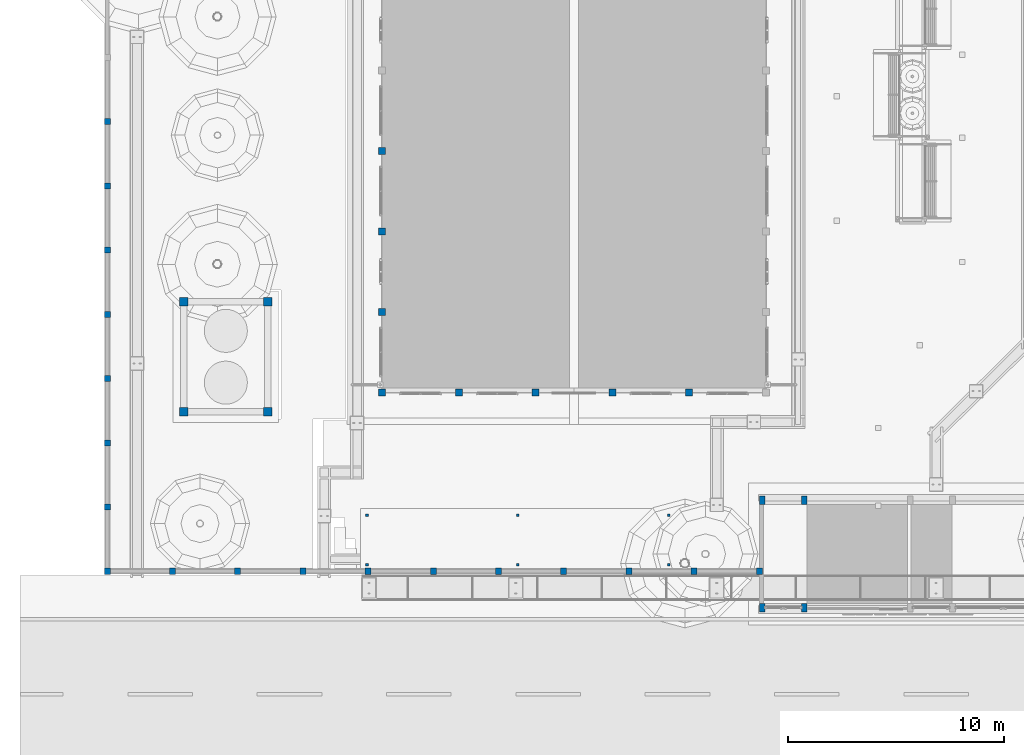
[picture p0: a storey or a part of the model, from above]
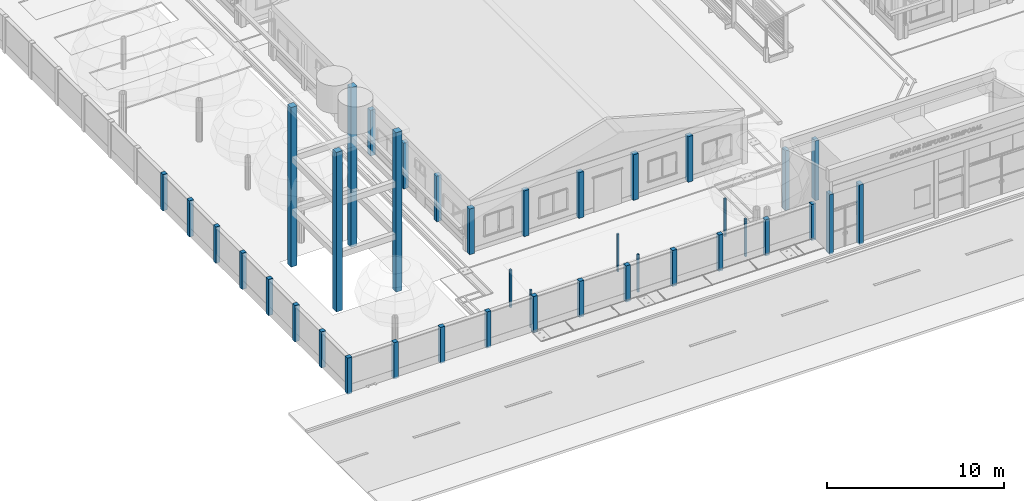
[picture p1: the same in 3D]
Properties of the parts of a building model (IFC4)

# File
Description: ViewDefinition [CoordinationView]
Time: 2026-11-03T15:19:36
Written by: IfcOpenShell 0.9.0post1+b5e509b
Made in: IfcOpenShell 0.9.0post1+b5e509b

# IfcBuildingStorey, NIVEL 1 (NPT +0.00)
In: Hogar de Refugio Temporal
Elevation: 0 m

# IfcBeam: Viga (200)
In: NIVEL 1 (NPT +0.00)
PredefinedType: BEAM
Pset_HogarRefugio - Categoria: Viga
Name | Grupo = Group | Material
E-01_viga | E-01 | TP1
E-02_viga | E-02 | TP1
E-03_viga | E-03 | TP1
E-04_viga | E-04 | TP1
E-05_viga | E-05 | TP1
E-06_viga | E-06 | TP1
E-08_viga | E-08 | TP1
E-07_viga | E-07 | TP1
E-09_viga | E-09 | TP1
2 x travesano | Losa deportiva | blanco
14 x arco | Losa deportiva | acero
133 x diag | Losa deportiva | acero
2 x viga_long | Losa deportiva | acero
oe01_viga | Obras exteriores | TP1
oe01_cielo | Obras exteriores | TP2
oe01_viga_post | Obras exteriores | TP1
8 x tanque_viga | Obras exteriores | concreto_gris
2 x columpio_viga | Obras exteriores | juego_rojo
9 x oc01_viga | Obras exteriores | estructura_acero
18 x oc01_correa | Obras exteriores | estructura_acero

# IfcBuildingElementProxy: Asta de banderas (3)
In: NIVEL 1 (NPT +0.00)
Pset_HogarRefugio - Grupo: Obras exteriores; Categoria: Asta de banderas
Group: Obras exteriores
Name | Material
2 x bandera | bandera_roja
bandera | bandera_blanca

# IfcBuildingElementProxy: Elemento (6)
In: NIVEL 1 (NPT +0.00)
Pset_HogarRefugio - Categoria: Elemento
Name | Grupo = Group | Material
Torus | Losa deportiva | linea
2 x Cylinder | Obras exteriores | negro
3 x Cylinder | Obras exteriores | aluminio_claro

# IfcBuildingElementProxy: Letras "HOGAR DE REFUGIO TEMPORAL", letrero
In: NIVEL 1 (NPT +0.00)
Pset_HogarRefugio - Grupo: Obras exteriores; Categoria: Letras "HOGAR DE REFUGIO TEMPORAL"; Material: aluminio_claro
Group: Obras exteriores

# IfcBuildingElementProxy: Losa deportiva y vía (111)
In: NIVEL 1 (NPT +0.00)
Pset_HogarRefugio - Categoria: Losa deportiva y vía
Name | Grupo = Group | Material
pista | Terreno | asfalto
92 x linea_carril | Terreno | linea
cancha | Losa deportiva | cancha
5 x linea_cancha | Losa deportiva | linea
2 x area | Losa deportiva | cancha_borde
6 x linea_area | Losa deportiva | linea
2 x tablero | Losa deportiva | blanco
2 x brazo | Losa deportiva | acero

# IfcColumn: Columna (386)
In: NIVEL 1 (NPT +0.00)
PredefinedType: COLUMN
Pset_HogarRefugio - Categoria: Columna
Name | Grupo = Group | Material
26 x E-01_col | E-01 | TP1
14 x E-02_col | E-02 | TP1
16 x E-03_col | E-03 | TP1
30 x E-04_col | E-04 | TP1
28 x E-05_col | E-05 | TP1
20 x E-06_col | E-06 | TP1
20 x E-08_col | E-08 | TP1
30 x E-07_col | E-07 | TP1
14 x E-09_col | E-09 | TP1
4 x poste_arco | Losa deportiva | blanco
2 x poste_basquet | Losa deportiva | acero
14 x columna_losa | Losa deportiva | acero
5 x oe01_col | Obras exteriores | TP1
5 x oe01_col_post | Obras exteriores | TP1
6 x poste_autos | Obras exteriores | acero
6 x poste_motos | Obras exteriores | acero
4 x tanque_col | Obras exteriores | concreto_gris
124 x columna_cerco | Obras exteriores | TP2
18 x oc01_columna | Obras exteriores | estructura_acero

# IfcColumn: Falsa columna (45)
In: NIVEL 1 (NPT +0.00)
PredefinedType: COLUMN
Pset_HogarRefugio - Categoria: Falsa columna; Material: concreto_gris
Name | Grupo = Group
9 x oc01_falsa_columna | Obras exteriores
36 x falsa_columna | Drenaje

# IfcDistributionChamberElement: Tapa ciega de registro del colector (28)
In: NIVEL 1 (NPT +0.00)
PredefinedType: INSPECTIONCHAMBER; Group: Drenaje
Pset_HogarRefugio - Grupo: Drenaje; Categoria: Tapa ciega de registro del colector
Name | Material
7 x tapa_junta | negro
7 x tapa_ciega | tapa_concreto
14 x tapa_asa | acero

# IfcDistributionChamberElement: Tapa de inspección (68)
In: NIVEL 1 (NPT +0.00)
PredefinedType: INSPECTIONCHAMBER; Group: Drenaje
Pset_HogarRefugio - Grupo: Drenaje; Categoria: Tapa de inspección
Name | Material
17 x tapa_insp_junta | negro
17 x tapa_inspeccion | tapa_inspeccion
34 x tapa_insp_asa | acero

# IfcDoor: Puerta (108)
In: NIVEL 1 (NPT +0.00)
PredefinedType: DOOR
Pset_HogarRefugio - Categoria: Puerta
Name | Grupo = Group | Material
2 x E-01_pp | E-01 | vidrio
2 x E-01_pp_marco | E-01 | TP1
2 x E-01_p1 | E-01 | puerta
2 x E-01_p1_marco | E-01 | TP1
2 x E-01_p4 | E-01 | puerta
2 x E-01_p4_marco | E-01 | TP1
2 x E-02_pp | E-02 | puerta
2 x E-02_pp_marco | E-02 | TP1
2 x E-02_p1 | E-02 | puerta
2 x E-02_p1_marco | E-02 | TP1
2 x E-03_p1 | E-03 | puerta
2 x E-03_p1_marco | E-03 | TP1
2 x E-03_pp | E-03 | puerta
2 x E-03_pp_marco | E-03 | TP1
2 x E-04_pp | E-04 | puerta
2 x E-04_pp_marco | E-04 | TP1
2 x E-04_p1 | E-04 | puerta
2 x E-04_p1_marco | E-04 | TP1
2 x E-04_p4 | E-04 | puerta
2 x E-04_p4_marco | E-04 | TP1
2 x E-04_p7 | E-04 | puerta
2 x E-04_p7_marco | E-04 | TP1
2 x E-05_pp | E-05 | vidrio
2 x E-05_pp_marco | E-05 | TP1
2 x E-05_p1 | E-05 | puerta
2 x E-05_p1_marco | E-05 | TP1
2 x E-05_p4 | E-05 | puerta
2 x E-05_p4_marco | E-05 | TP1
2 x E-05_p7 | E-05 | puerta
2 x E-05_p7_marco | E-05 | TP1
2 x E-06_p1 | E-06 | puerta
2 x E-06_p1_marco | E-06 | TP1
2 x E-06_p4 | E-06 | puerta
2 x E-06_p4_marco | E-06 | TP1
2 x E-06_pp | E-06 | puerta
2 x E-06_pp_marco | E-06 | TP1
2 x E-08_p1 | E-08 | puerta
2 x E-08_p1_marco | E-08 | TP1
2 x E-08_p4 | E-08 | puerta
2 x E-08_p4_marco | E-08 | TP1
2 x E-08_pp | E-08 | puerta
2 x E-08_pp_marco | E-08 | TP1
2 x E-07_pp | E-07 | puerta
2 x E-07_pp_marco | E-07 | TP1
2 x E-07_p1 | E-07 | puerta
2 x E-07_p1_marco | E-07 | TP1
2 x E-07_p4 | E-07 | puerta
2 x E-07_p4_marco | E-07 | TP1
2 x E-07_p7 | E-07 | puerta
2 x E-07_p7_marco | E-07 | TP1
2 x E-09_pp | E-09 | puerta
2 x E-09_pp_marco | E-09 | TP1
2 x E-09_p1 | E-09 | puerta
2 x E-09_p1_marco | E-09 | TP1

# IfcDoor: Puerta / portón (35)
In: NIVEL 1 (NPT +0.00)
PredefinedType: DOOR; Group: Obras exteriores
Pset_HogarRefugio - Grupo: Obras exteriores; Categoria: Puerta / portón
Name | Material
2 x oe01_porton_peatonal_plancha | plancha_metalica
10 x oe01_porton_peatonal_m | negro
2 x oe01_porton_peatonal_manija | acero
oe01_puerta_plancha | plancha_metalica
5 x oe01_puerta_m | negro
oe01_puerta_manija | acero
2 x oe01_porton_vehicular_plancha | plancha_metalica
10 x oe01_porton_vehicular_m | negro
2 x oe01_porton_vehicular_manija | acero

# IfcFurnishingElement: Mobiliario exterior / juegos (211)
In: NIVEL 1 (NPT +0.00)
Pset_HogarRefugio - Grupo: Obras exteriores; Categoria: Mobiliario exterior / juegos
Group: Obras exteriores
Name | Material
14 x banca_base | concreto_gris
14 x banca_asiento | madera
5 x balancin_base | juego_azul
5 x balancin_tabla | juego_rojo
10 x balancin_manija | plastico_amarillo
2 x tobogan_escalera | juego_azul
4 x tobogan_poste | juego_azul
5 x peldano | acero
tobogan_plataforma | juego_rojo
2 x baranda | juego_azul
resbaladera | plastico_amarillo
2 x resbaladera_borde | plastico_amarillo
8 x columpio_pata | juego_rojo
4 x columpio_asiento | plastico_amarillo
8 x cadena | acero
54 x oc01_celosia | madera
45 x oc01_asiento | madera
27 x oc01_pata | estructura_acero

# IfcGeographicElement: Árbol (60)
In: NIVEL 1 (NPT +0.00)
Pset_HogarRefugio - Grupo: Arboles; Categoria: Árbol
Group: Arboles
Name | Material
30 x arbol_tronco | tronco
30 x arbol_copa | hojas1

# IfcGeographicElement: Área verde (4)
In: NIVEL 1 (NPT +0.00)
PredefinedType: TERRAIN; Group: Pasto
Pset_HogarRefugio - Grupo: Pasto; Categoria: Área verde; Material: pasto
Name
pasto_0
pasto_jardinera_0
pasto_jardinera_1
pasto_jardinera_2

# IfcPipeFitting: Rejilla metálica de cuneta y sumidero, rejillas_cunetas
In: NIVEL 1 (NPT +0.00)
Pset_HogarRefugio - Grupo: Drenaje; Categoria: Rejilla metálica de cuneta y sumidero; Material: galvanizado
Group: Drenaje

# IfcPipeSegment: Canaleta (27)
In: NIVEL 1 (NPT +0.00)
PredefinedType: GUTTER
Pset_HogarRefugio - Categoria: Canaleta
Name | Grupo = Group | Material
2 x E-01_canaleta | E-01 | canaleta_galv
2 x E-02_canaleta | E-02 | canaleta_galv
2 x E-03_canaleta | E-03 | canaleta_galv
2 x E-04_canaleta | E-04 | canaleta_galv
2 x E-05_canaleta | E-05 | canaleta_galv
2 x E-06_canaleta | E-06 | canaleta_galv
2 x E-08_canaleta | E-08 | canaleta_galv
2 x E-07_canaleta | E-07 | canaleta_galv
2 x E-09_canaleta | E-09 | canaleta_galv
9 x oc01_canaleta | Obras exteriores | galvanizado

# IfcPipeSegment: Colector frontal b=0.80 (losa-vereda) (23)
In: NIVEL 1 (NPT +0.00)
PredefinedType: CULVERT; Group: Drenaje
Pset_HogarRefugio - Grupo: Drenaje; Categoria: Colector frontal b=0.80 (losa-vereda)
Name | Material
colector_losa | concreto_cuneta
2 x junta_colector | negro
20 x junta_losa | negro

# IfcPipeSegment: Cuneta de concreto b=0.40 (2)
In: NIVEL 1 (NPT +0.00)
PredefinedType: GUTTER; Group: Drenaje
Pset_HogarRefugio - Grupo: Drenaje; Categoria: Cuneta de concreto b=0.40
Name | Material
cunetas_muros | concreto_cuneta
cunetas_fondo | cuneta_fondo

# IfcPipeSegment: Montante PVC 4" (189)
In: NIVEL 1 (NPT +0.00)
PredefinedType: RIGIDSEGMENT; Group: Obras exteriores
Pset_HogarRefugio - Grupo: Obras exteriores; Categoria: Montante PVC 4"
Name | Material
36 x montante_boquilla | pvc
36 x montante_desvio | pvc
36 x montante_bajada | pvc
72 x montante_abrazadera | galvanizado
9 x oc01_bajada | pvc

# IfcRoof: Cobertura (32)
In: NIVEL 1 (NPT +0.00)
Pset_HogarRefugio - Categoria: Cobertura
Name | Grupo = Group | Material
E-01_techo | E-01 | calamina_y
E-01_cumbrera | E-01 | aluminio_claro
E-02_techo | E-02 | calamina_y
E-02_cumbrera | E-02 | aluminio_claro
E-03_techo | E-03 | calamina_x
E-03_cumbrera | E-03 | aluminio_claro
E-04_techo | E-04 | calamina_y
E-04_cumbrera | E-04 | aluminio_claro
E-05_techo | E-05 | calamina_y
E-05_cumbrera | E-05 | aluminio_claro
E-06_techo | E-06 | calamina_x
E-06_cumbrera | E-06 | aluminio_claro
E-08_techo | E-08 | calamina_x
E-08_cumbrera | E-08 | aluminio_claro
E-07_techo | E-07 | calamina_y
E-07_cumbrera | E-07 | aluminio_claro
E-09_techo | E-09 | calamina_y
E-09_cumbrera | E-09 | aluminio_claro
cubierta_losa | Losa deportiva | calamina_y
oe01_techo | Obras exteriores | calamina_x
techo_autos | Obras exteriores | calamina_y
techo_motos | Obras exteriores | calamina_y
tobogan_techo | Obras exteriores | juego_verde
3 x oc01_cobertura_aluzinc | Obras exteriores | calamina_y
6 x oc01_cobertura_aluzinc | Obras exteriores | calamina_x

# IfcSlab: Piso / losa (32)
In: NIVEL 1 (NPT +0.00)
PredefinedType: FLOOR
Pset_HogarRefugio - Categoria: Piso / losa
Name | Grupo = Group | Material
vereda_ext | Terreno | vereda
vereda_otra | Terreno | vereda
sardinel | Terreno | blanco
vereda_0 | Terreno | vereda
vereda_1 | Terreno | vereda
vereda_2 | Terreno | vereda
vereda_3 | Terreno | vereda
vereda_4 | Terreno | vereda
vereda_5 | Terreno | vereda
vereda_6 | Terreno | vereda
pavimento_concreto | Terreno | pavimento
E-01_piso | E-01 | vereda
E-02_piso | E-02 | vereda
E-03_piso | E-03 | vereda
E-04_piso | E-04 | vereda
E-05_piso | E-05 | vereda
E-06_piso | E-06 | vereda
E-08_piso | E-08 | vereda
E-07_piso | E-07 | vereda
E-09_piso | E-09 | vereda
losa | Losa deportiva | cancha_borde
oe01_piso | Obras exteriores | vereda
losa_autos | Obras exteriores | concreto_gris
losa_motos | Obras exteriores | concreto_gris
tanque_losa | Obras exteriores | concreto_gris
plaza_piso | Obras exteriores | adoquin
asta_base | Obras exteriores | concreto_gris
juegos_arena | Obras exteriores | arena
4 x juegos_sardinel | Obras exteriores | concreto_gris

# IfcWall: Muro (64)
In: NIVEL 1 (NPT +0.00)
Pset_HogarRefugio - Categoria: Muro
Name | Grupo = Group | Material
E-01_muro | E-01 | TP2
E-01_zocalo | E-01 | concreto_gris
2 x E-01_hastial | E-01 | TP3
E-02_muro | E-02 | TP2
E-02_zocalo | E-02 | concreto_gris
2 x E-02_hastial | E-02 | TP3
E-03_muro | E-03 | TP2
E-03_zocalo | E-03 | concreto_gris
2 x E-03_hastial | E-03 | TP3
E-04_muro | E-04 | TP2
E-04_zocalo | E-04 | concreto_gris
2 x E-04_hastial | E-04 | TP3
E-05_muro | E-05 | TP2
E-05_zocalo | E-05 | concreto_gris
2 x E-05_hastial | E-05 | TP3
E-06_muro | E-06 | TP2
E-06_zocalo | E-06 | concreto_gris
2 x E-06_hastial | E-06 | TP3
E-08_muro | E-08 | TP2
E-08_zocalo | E-08 | concreto_gris
2 x E-08_hastial | E-08 | TP3
E-07_muro | E-07 | TP2
E-07_zocalo | E-07 | concreto_gris
2 x E-07_hastial | E-07 | TP3
E-09_muro | E-09 | TP2
E-09_zocalo | E-09 | concreto_gris
2 x E-09_hastial | E-09 | TP3
oe01_parapeto | Obras exteriores | TP3
oe01_parapeto_post | Obras exteriores | TP3
2 x oe01_lateral | Obras exteriores | TP2
oe01_muro_m1 | Obras exteriores | TP2
oe01_zocalo | Obras exteriores | concreto_gris
oe01_caseta | Obras exteriores | TP2
5 x cerco_muro | Obras exteriores | TP3
5 x cerco_zocalo | Obras exteriores | TP2
5 x cerco_remate | Obras exteriores | concreto_gris
3 x jardinera | Obras exteriores | concreto_gris
3 x jardinera_tierra | Obras exteriores | tierra_jardinera

# IfcWasteTerminal: Sumidero con rejilla (30)
In: NIVEL 1 (NPT +0.00)
PredefinedType: GULLYTRAP; Group: Drenaje
Pset_HogarRefugio - Grupo: Drenaje; Categoria: Sumidero con rejilla; Material: cuneta_fondo

# IfcWindow: Ventana (864)
In: NIVEL 1 (NPT +0.00)
PredefinedType: WINDOW
Pset_HogarRefugio - Categoria: Ventana
Name | Grupo = Group | Material
2 x E-01_vg0_vid | E-01 | vidrio
8 x E-01_vg0_m | E-01 | aluminio
2 x E-01_vg0_alf | E-01 | concreto_gris
2 x E-01_vg1_vid | E-01 | vidrio
8 x E-01_vg1_m | E-01 | aluminio
2 x E-01_vg1_alf | E-01 | concreto_gris
2 x E-01_vg3_vid | E-01 | vidrio
8 x E-01_vg3_m | E-01 | aluminio
2 x E-01_vg3_alf | E-01 | concreto_gris
2 x E-01_vg4_vid | E-01 | vidrio
8 x E-01_vg4_m | E-01 | aluminio
2 x E-01_vg4_alf | E-01 | concreto_gris
2 x E-01_v0_vid | E-01 | vidrio
8 x E-01_v0_m | E-01 | aluminio
2 x E-01_v0_alf | E-01 | concreto_gris
2 x E-01_vt1_vid | E-01 | vidrio
8 x E-01_vt1_m | E-01 | aluminio
2 x E-01_vt1_alf | E-01 | concreto_gris
2 x E-01_v2_vid | E-01 | vidrio
8 x E-01_v2_m | E-01 | aluminio
2 x E-01_v2_alf | E-01 | concreto_gris
2 x E-01_v3_vid | E-01 | vidrio
8 x E-01_v3_m | E-01 | aluminio
2 x E-01_v3_alf | E-01 | concreto_gris
2 x E-01_vt4_vid | E-01 | vidrio
8 x E-01_vt4_m | E-01 | aluminio
2 x E-01_vt4_alf | E-01 | concreto_gris
2 x E-01_v5_vid | E-01 | vidrio
8 x E-01_v5_m | E-01 | aluminio
2 x E-01_v5_alf | E-01 | concreto_gris
2 x E-02_vg0_vid | E-02 | vidrio
8 x E-02_vg0_m | E-02 | aluminio
2 x E-02_vg0_alf | E-02 | concreto_gris
2 x E-02_v0_vid | E-02 | vidrio
8 x E-02_v0_m | E-02 | aluminio
2 x E-02_v0_alf | E-02 | concreto_gris
2 x E-02_vt1_vid | E-02 | vidrio
8 x E-02_vt1_m | E-02 | aluminio
2 x E-02_vt1_alf | E-02 | concreto_gris
2 x E-02_v2_vid | E-02 | vidrio
8 x E-02_v2_m | E-02 | aluminio
2 x E-02_v2_alf | E-02 | concreto_gris
2 x E-03_v0_vid | E-03 | vidrio
8 x E-03_v0_m | E-03 | aluminio
2 x E-03_v0_alf | E-03 | concreto_gris
2 x E-03_vt1_vid | E-03 | vidrio
8 x E-03_vt1_m | E-03 | aluminio
2 x E-03_vt1_alf | E-03 | concreto_gris
2 x E-03_v2_vid | E-03 | vidrio
8 x E-03_v2_m | E-03 | aluminio
2 x E-03_v2_alf | E-03 | concreto_gris
2 x E-03_v3_vid | E-03 | vidrio
8 x E-03_v3_m | E-03 | aluminio
2 x E-03_v3_alf | E-03 | concreto_gris
2 x E-03_vg0_vid | E-03 | vidrio
8 x E-03_vg0_m | E-03 | aluminio
2 x E-03_vg0_alf | E-03 | concreto_gris
2 x E-04_vg0_vid | E-04 | vidrio
8 x E-04_vg0_m | E-04 | aluminio
2 x E-04_vg0_alf | E-04 | concreto_gris
2 x E-04_vg2_vid | E-04 | vidrio
8 x E-04_vg2_m | E-04 | aluminio
2 x E-04_vg2_alf | E-04 | concreto_gris
2 x E-04_v0_vid | E-04 | vidrio
8 x E-04_v0_m | E-04 | aluminio
2 x E-04_v0_alf | E-04 | concreto_gris
2 x E-04_vt1_vid | E-04 | vidrio
8 x E-04_vt1_m | E-04 | aluminio
2 x E-04_vt1_alf | E-04 | concreto_gris
2 x E-04_v2_vid | E-04 | vidrio
8 x E-04_v2_m | E-04 | aluminio
2 x E-04_v2_alf | E-04 | concreto_gris
2 x E-04_v3_vid | E-04 | vidrio
8 x E-04_v3_m | E-04 | aluminio
2 x E-04_v3_alf | E-04 | concreto_gris
2 x E-04_vt4_vid | E-04 | vidrio
8 x E-04_vt4_m | E-04 | aluminio
2 x E-04_vt4_alf | E-04 | concreto_gris
2 x E-04_v5_vid | E-04 | vidrio
8 x E-04_v5_m | E-04 | aluminio
2 x E-04_v5_alf | E-04 | concreto_gris
2 x E-04_v6_vid | E-04 | vidrio
8 x E-04_v6_m | E-04 | aluminio
2 x E-04_v6_alf | E-04 | concreto_gris
2 x E-04_vt7_vid | E-04 | vidrio
8 x E-04_vt7_m | E-04 | aluminio
2 x E-04_vt7_alf | E-04 | concreto_gris
2 x E-04_v8_vid | E-04 | vidrio
8 x E-04_v8_m | E-04 | aluminio
2 x E-04_v8_alf | E-04 | concreto_gris
2 x E-04_v9_vid | E-04 | vidrio
8 x E-04_v9_m | E-04 | aluminio
2 x E-04_v9_alf | E-04 | concreto_gris
2 x E-05_vg0_vid | E-05 | vidrio
8 x E-05_vg0_m | E-05 | aluminio
2 x E-05_vg0_alf | E-05 | concreto_gris
2 x E-05_vg1_vid | E-05 | vidrio
8 x E-05_vg1_m | E-05 | aluminio
2 x E-05_vg1_alf | E-05 | concreto_gris
2 x E-05_vg3_vid | E-05 | vidrio
8 x E-05_vg3_m | E-05 | aluminio
2 x E-05_vg3_alf | E-05 | concreto_gris
2 x E-05_v0_vid | E-05 | vidrio
8 x E-05_v0_m | E-05 | aluminio
2 x E-05_v0_alf | E-05 | concreto_gris
2 x E-05_vt1_vid | E-05 | vidrio
8 x E-05_vt1_m | E-05 | aluminio
2 x E-05_vt1_alf | E-05 | concreto_gris
2 x E-05_v2_vid | E-05 | vidrio
8 x E-05_v2_m | E-05 | aluminio
2 x E-05_v2_alf | E-05 | concreto_gris
2 x E-05_v3_vid | E-05 | vidrio
8 x E-05_v3_m | E-05 | aluminio
2 x E-05_v3_alf | E-05 | concreto_gris
2 x E-05_vt4_vid | E-05 | vidrio
8 x E-05_vt4_m | E-05 | aluminio
2 x E-05_vt4_alf | E-05 | concreto_gris
2 x E-05_v5_vid | E-05 | vidrio
8 x E-05_v5_m | E-05 | aluminio
2 x E-05_v5_alf | E-05 | concreto_gris
2 x E-05_v6_vid | E-05 | vidrio
8 x E-05_v6_m | E-05 | aluminio
2 x E-05_v6_alf | E-05 | concreto_gris
2 x E-05_vt7_vid | E-05 | vidrio
8 x E-05_vt7_m | E-05 | aluminio
2 x E-05_vt7_alf | E-05 | concreto_gris
2 x E-06_v0_vid | E-06 | vidrio
8 x E-06_v0_m | E-06 | aluminio
2 x E-06_v0_alf | E-06 | concreto_gris
2 x E-06_vt1_vid | E-06 | vidrio
8 x E-06_vt1_m | E-06 | aluminio
2 x E-06_vt1_alf | E-06 | concreto_gris
2 x E-06_v2_vid | E-06 | vidrio
8 x E-06_v2_m | E-06 | aluminio
2 x E-06_v2_alf | E-06 | concreto_gris
2 x E-06_v3_vid | E-06 | vidrio
8 x E-06_v3_m | E-06 | aluminio
2 x E-06_v3_alf | E-06 | concreto_gris
2 x E-06_vt4_vid | E-06 | vidrio
8 x E-06_vt4_m | E-06 | aluminio
2 x E-06_vt4_alf | E-06 | concreto_gris
2 x E-06_vg0_vid | E-06 | vidrio
8 x E-06_vg0_m | E-06 | aluminio
2 x E-06_vg0_alf | E-06 | concreto_gris
2 x E-06_vg2_vid | E-06 | vidrio
8 x E-06_vg2_m | E-06 | aluminio
2 x E-06_vg2_alf | E-06 | concreto_gris
2 x E-08_v0_vid | E-08 | vidrio
8 x E-08_v0_m | E-08 | aluminio
2 x E-08_v0_alf | E-08 | concreto_gris
2 x E-08_vt1_vid | E-08 | vidrio
8 x E-08_vt1_m | E-08 | aluminio
2 x E-08_vt1_alf | E-08 | concreto_gris
2 x E-08_v2_vid | E-08 | vidrio
8 x E-08_v2_m | E-08 | aluminio
2 x E-08_v2_alf | E-08 | concreto_gris
2 x E-08_v3_vid | E-08 | vidrio
8 x E-08_v3_m | E-08 | aluminio
2 x E-08_v3_alf | E-08 | concreto_gris
2 x E-08_vt4_vid | E-08 | vidrio
8 x E-08_vt4_m | E-08 | aluminio
2 x E-08_vt4_alf | E-08 | concreto_gris
2 x E-08_vg0_vid | E-08 | vidrio
8 x E-08_vg0_m | E-08 | aluminio
2 x E-08_vg0_alf | E-08 | concreto_gris
2 x E-08_vg2_vid | E-08 | vidrio
8 x E-08_vg2_m | E-08 | aluminio
2 x E-08_vg2_alf | E-08 | concreto_gris
2 x E-07_vg0_vid | E-07 | vidrio
8 x E-07_vg0_m | E-07 | aluminio
2 x E-07_vg0_alf | E-07 | concreto_gris
2 x E-07_vg2_vid | E-07 | vidrio
8 x E-07_vg2_m | E-07 | aluminio
2 x E-07_vg2_alf | E-07 | concreto_gris
2 x E-07_v0_vid | E-07 | vidrio
8 x E-07_v0_m | E-07 | aluminio
2 x E-07_v0_alf | E-07 | concreto_gris
2 x E-07_vt1_vid | E-07 | vidrio
8 x E-07_vt1_m | E-07 | aluminio
2 x E-07_vt1_alf | E-07 | concreto_gris
2 x E-07_v2_vid | E-07 | vidrio
8 x E-07_v2_m | E-07 | aluminio
2 x E-07_v2_alf | E-07 | concreto_gris
2 x E-07_v3_vid | E-07 | vidrio
8 x E-07_v3_m | E-07 | aluminio
2 x E-07_v3_alf | E-07 | concreto_gris
2 x E-07_vt4_vid | E-07 | vidrio
8 x E-07_vt4_m | E-07 | aluminio
2 x E-07_vt4_alf | E-07 | concreto_gris
2 x E-07_v5_vid | E-07 | vidrio
8 x E-07_v5_m | E-07 | aluminio
2 x E-07_v5_alf | E-07 | concreto_gris
2 x E-07_v6_vid | E-07 | vidrio
8 x E-07_v6_m | E-07 | aluminio
2 x E-07_v6_alf | E-07 | concreto_gris
2 x E-07_vt7_vid | E-07 | vidrio
8 x E-07_vt7_m | E-07 | aluminio
2 x E-07_vt7_alf | E-07 | concreto_gris
2 x E-07_v8_vid | E-07 | vidrio
8 x E-07_v8_m | E-07 | aluminio
2 x E-07_v8_alf | E-07 | concreto_gris
2 x E-07_v9_vid | E-07 | vidrio
8 x E-07_v9_m | E-07 | aluminio
2 x E-07_v9_alf | E-07 | concreto_gris
2 x E-09_vg0_vid | E-09 | vidrio
8 x E-09_vg0_m | E-09 | aluminio
2 x E-09_vg0_alf | E-09 | concreto_gris
2 x E-09_v0_vid | E-09 | vidrio
8 x E-09_v0_m | E-09 | aluminio
2 x E-09_v0_alf | E-09 | concreto_gris
2 x E-09_vt1_vid | E-09 | vidrio
8 x E-09_vt1_m | E-09 | aluminio
2 x E-09_vt1_alf | E-09 | concreto_gris
2 x E-09_v2_vid | E-09 | vidrio
8 x E-09_v2_m | E-09 | aluminio
2 x E-09_v2_alf | E-09 | concreto_gris

# IfcWindow: Ventana / paño metálico (18)
In: NIVEL 1 (NPT +0.00)
PredefinedType: WINDOW; Group: Obras exteriores
Pset_HogarRefugio - Grupo: Obras exteriores; Categoria: Ventana / paño metálico
Name | Material
oe01_celosia1 | plancha_metalica
2 x oe01_celosia1_marco | negro
oe01_ventana | plancha_metalica
2 x oe01_ventana_marco | negro
oe01_celosia3 | plancha_metalica
2 x oe01_celosia3_marco | negro
3 x oe01_celosia4 | plancha_metalica
6 x oe01_celosia4_marco | negro
